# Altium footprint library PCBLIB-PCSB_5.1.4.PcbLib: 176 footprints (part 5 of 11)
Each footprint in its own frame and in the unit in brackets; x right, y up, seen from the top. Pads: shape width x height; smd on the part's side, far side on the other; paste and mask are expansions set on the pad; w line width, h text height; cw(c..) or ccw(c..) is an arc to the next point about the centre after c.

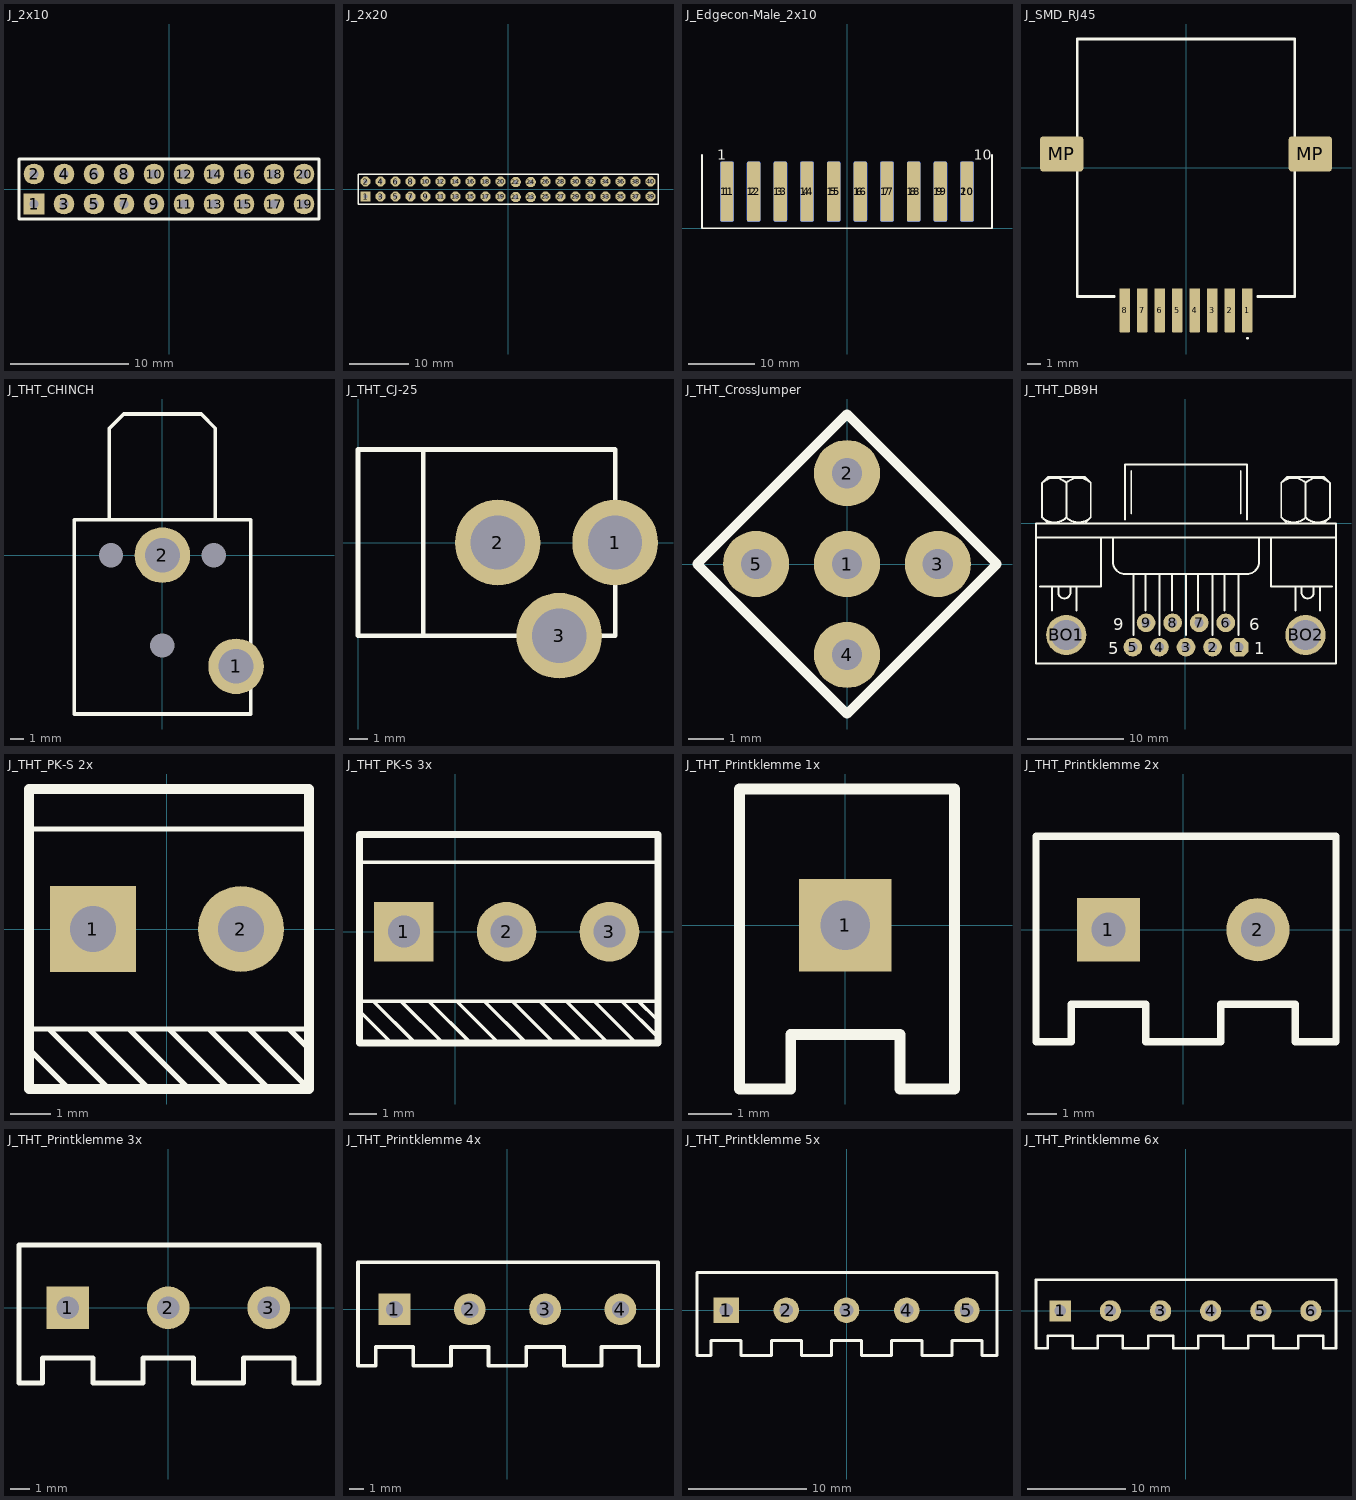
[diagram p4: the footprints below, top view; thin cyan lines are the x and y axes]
## J_2x10 [mm] "LB-2024-4-19"
pads (20):
  rect 1.75x1.75 hole 0.75: 1(-11.43,-1.27)
  round 1.75 hole 0.75: 2(-11.43,1.27) 3(-8.89,-1.27) 4(-8.89,1.27) 5(-6.35,-1.27) 6(-6.35,1.27) 7(-3.81,-1.27) 8(-3.81,1.27) 9(-1.27,-1.27) 10(-1.27,1.27) 11(1.27,-1.27) 12(1.27,1.27) 13(3.81,-1.27) 14(3.81,1.27) 15(6.35,-1.27) 16(6.35,1.27) 17(8.89,-1.27) 18(8.89,1.27) 19(11.43,-1.27) 20(11.43,1.27)
Top Overlay:
  lines w0.254: -12.7,-2.54 12.7,-2.54 12.7,2.54 -12.7,2.54 -12.7,-2.54

## J_2x20 [mm] "LB-2024-4-19"
pads (40):
  rect 1.75x1.75 hole 0.75: 1(-24.13,-1.224)
  round 1.75 hole 0.75: 2(-24.13,1.316) 3(-21.59,-1.224) 4(-21.59,1.316) 5(-19.05,-1.224) 6(-19.05,1.316) 7(-16.51,-1.224) 8(-16.51,1.316) 9(-13.97,-1.224) 10(-13.97,1.316) 11(-11.43,-1.224) 12(-11.43,1.316) 13(-8.89,-1.224) 14(-8.89,1.316) 15(-6.35,-1.224) 16(-6.35,1.316) 17(-3.81,-1.224) 18(-3.81,1.316) 19(-1.27,-1.224) 20(-1.27,1.316) 21(1.296,-1.316) 22(1.296,1.224) 23(3.836,-1.316) 24(3.836,1.224) 25(6.35,-1.224) 26(6.35,1.316) 27(8.89,-1.224) 28(8.89,1.316) 29(11.43,-1.224) 30(11.43,1.316) 31(13.97,-1.224) 32(13.97,1.316) 33(16.51,-1.224) 34(16.51,1.316) 35(19.05,-1.224) 36(19.05,1.316) 37(21.59,-1.224) 38(21.59,1.316) 39(24.13,-1.224) 40(24.13,1.316)
Top Overlay:
  lines w0.254: -25.4,-2.494 25.4,-2.494 25.4,2.586 -25.4,2.586 -25.4,-2.494

## J_Edgecon-Male_2x10 [mm] "PS-2024-06-15"
pads (20):
  rrect25% 2x9 smd paste-0.02 mask+0.05: 1(-18,5.5) 2(-14,5.5) 3(-10,5.5) 4(-6,5.5) 5(-2,5.5) 6(2,5.5) 7(6,5.5) 8(10,5.5) 9(14,5.5) 10(18,5.5)
  rrect25% 2x9 smd far side paste-0.02 mask+0.05: 11(-18,5.5) 12(-14,5.5) 13(-10,5.5) 14(-6,5.5) 15(-2,5.5) 16(2,5.5) 17(6,5.5) 18(10,5.5) 19(14,5.5) 20(18,5.5)
Bottom Layer:
  lines w0.254: -18,8.75 -18,9
Top Overlay:
  lines w0.254: -21.75,11 -21.75,10.75 -21.75,0 0,0 21.75,0 21.75,11
  text "1" at -19.496,10.254 h1.52
  text "10" at 19.004,10.254 h1.52
Bottom Overlay:
  text "11" at -18.754,10.254 h1.52
  text "20" at 21.496,10.254 h1.52

## J_SMD_RJ45 [mm] "LB-2024-05-31"
pads (10):
  rrect15% 0.76x3.185 smd paste-0.02 mask+0.05: 1(4.445,-10.325) 2(3.175,-10.325) 3(1.905,-10.325) 4(0.635,-10.325) 5(-0.635,-10.325) 6(-1.905,-10.325) 7(-3.175,-10.325) 8(-4.445,-10.325)
  rrect15% 3.12x2.54 smd paste-0.02 mask+0.05: MP(-9,1) MP(9,1)
Top Overlay:
  lines w0.1: 4.445,-12.4 cw(c4.445,-12.35) 4.445,-12.3 cw(c4.445,-12.35) 4.445,-12.4
  lines w0.2: -5.2,-9.325 -7.87,-9.325 -7.87,2.6 -7.87,5.8 -7.87,9.325 7.87,9.325 7.87,2.6 7.87,-9.325 5.2,-9.325

## J_THT_CHINCH [mm] "LB-2024-04-19"
pads (5):
  round 4 hole 2.5: 1(5.3,-8) 2(0,0)
  round 0.5 hole 1.75: 3(-3.7,0) 3(0,-6.5) 3(3.7,0)
Top Overlay:
  lines w0.254: -3.81,2.54 -3.81,9.144 -2.794,10.16 2.794,10.16 3.81,9.144 3.81,2.54 ; -6.35,-11.43 -6.35,2.54 -5.08,2.54 5.08,2.54 6.35,2.54 6.35,-11.43 -6.35,-11.43

## J_THT_CJ-25 [mm] "LB-2024-04-19"
height 1.7
pads (3):
  round 4.6 hole 2.9: 1(13.8,0) 2(7.5,0) 3(10.8,-5)
Top Overlay:
  lines w0.254: 3.5,-5 3.5,5 ; 0,-5 0,5 13.8,5 13.8,-5 0,-5

## J_THT_CrossJumper [mm] "LB-2024-04-19"
pads (5):
  round 1.85 hole 0.85: 1(0,0) 2(0,2.54) 3(2.54,0) 4(0,-2.54) 5(-2.54,0)
Top Overlay:
  lines w0.254: -4.191,0 0,-4.191 4.191,0 0,4.191 -4.191,0

## J_THT_DB9H [mm] "LB-2024-04-17"
pads (11):
  oct 1.95x1.95 hole 0.95: 1(5.6,-12.937)
  round 1.95 hole 0.95: 2(2.827,-12.937) 3(0.054,-12.937) 4(-2.718,-12.937) 5(-5.491,-12.937) 6(4.203,-10.397) 7(1.43,-10.397) 8(-1.343,-10.397) 9(-4.115,-10.397)
  round 4.2 hole 3.15: BO1(-12.455,-11.667) BO2(12.543,-11.667)
Top Overlay:
  lines w0.203: -15.609,-1.507 15.718,-1.507 ; -15.186,-6.587 -8.836,-6.587 -8.836,-1.507 ; -14.976,0.608 ccw(c-13.704,1.88) -12.432,0.608 ; -14.976,4.211 cw(c-13.704,2.938) -12.432,4.211 ; -14.339,-0.025 -14.974,0.61 -14.974,4.208 -14.339,4.843 -10.529,4.843 -9.894,4.208 -9.894,0.61 -10.529,-0.025 ; -13.916,-9.127 -13.916,-6.587 ; -13.281,-6.587 -13.281,-7.222 ccw(c-12.646,-7.222) -12.011,-7.222 -12.011,-6.587 ; -12.436,0.608 ccw(c-11.164,1.88) -9.892,0.608 ; -12.436,4.211 cw(c-11.164,2.938) -9.892,4.211 ; -12.434,0.61 -12.434,4.208 ; -11.376,-9.127 -11.376,-6.587 ; -7.566,-1.507 -7.566,-4.047 ccw(c-6.296,-4.047) -6.296,-5.317 6.404,-5.317 ccw(c6.404,-4.047) 7.674,-4.047 7.674,-1.507 ; -6.296,0.398 -6.296,6.113 6.404,6.113 6.404,0.398 ; -5.661,1.033 -5.661,5.478 ; -5.449,-11.667 -5.449,-5.317 ; -4.179,-9.127 -4.179,-5.317 ; -2.697,-11.667 -2.697,-5.317 ; -1.427,-9.127 -1.427,-5.317 ; 0.054,-11.667 0.054,-5.317 ; 1.324,-9.127 1.324,-5.317 ; 2.806,-11.667 2.806,-5.317 ; 4.076,-9.127 4.076,-8.915 4.076,-5.317 ; 5.558,-11.667 5.558,-5.317 ; 5.769,1.033 5.769,5.478 ; 8.944,-1.507 8.944,-6.587 15.294,-6.587 ; 10,0.608 ccw(c11.273,1.88) 12.545,0.608 ; 10,4.211 cw(c11.273,2.938) 12.545,4.211 ; 10.638,-0.025 10.003,0.61 10.003,4.208 10.638,4.843 14.448,4.843 15.083,4.208 15.083,0.61 14.448,-0.025 ; 11.484,-9.127 11.484,-6.587 ; 12.119,-6.587 12.119,-7.222 ccw(c12.754,-7.222) 13.389,-7.222 13.389,-6.587 ; 12.54,0.608 ccw(c13.813,1.88) 15.085,0.608 ; 12.54,4.211 cw(c13.813,2.938) 15.085,4.211 ; 12.543,0.61 12.543,4.208 ; 14.024,-9.127 14.024,-6.587 ; -15.609,-14.63 -15.609,-0.025 15.718,-0.025 15.718,-14.63 -15.609,-14.63
  text "9" at -7.566,-11.159 h1.27
  text "5" at -8.074,-13.699 h1.27
  text "1" at 7.166,-13.699 h1.27
  text "6" at 6.658,-11.159 h1.27

## J_THT_PK-S 2x [mm] "LB-2024-05-03g"
pads (2):
  rect 2.15x2.15 hole 1.15: 1(-1.85,0)
  round 2.15 hole 1.15: 2(1.85,0)
Top Overlay:
  lines w0.127: -3.45,2.5 3.55,2.5 ; -2.45,-4 -3.45,-3 -3.45,-2.5 3.55,-2.5 ; -1.95,-2.5 -0.45,-4 ; -1.45,-4 -2.95,-2.5 ; -0.95,-2.5 0.55,-4 ; 0.05,-2.5 1.55,-4 ; 1.05,-2.5 2.55,-4 ; 3.55,-4 2.05,-2.5 ; 3.55,-3 3.05,-2.5 ; -2.95,-2.5 -2.95,-2.5 ; 2.05,-2.5 2.05,-2.5 ; 3.05,-2.5 3.05,-2.5 ; 3.05,-2.5 3.05,-2.5
  lines w0.254: -3.45,-4 -3.45,2.365 -3.45,3.5 3.55,3.5 3.55,-4 -2.91,-4 -3.45,-4

## J_THT_PK-S 3x [mm] "LB-2024-05-03g"
pads (3):
  rect 2.15x2.15 hole 1.15: 1(-1.85,0)
  round 2.15 hole 1.15: 2(1.85,0) 3(5.55,0)
Top Overlay:
  lines w0.127: -3.5,-2.5 6.5,-2.5 7.3,-2.5 ; -3.45,2.5 7.3,2.5 ; -3.4,-2.9 -2.3,-4 ; -1.95,-2.5 -0.45,-4 ; -1.45,-4 -2.95,-2.5 ; -0.95,-2.5 0.55,-4 ; 0.05,-2.5 1.55,-4 ; 1.05,-2.5 2.55,-4 ; 3.55,-4 2.05,-2.5 ; 4,-2.5 5.425,-3.925 ; 4.575,-4.025 3.05,-2.5 ; 5,-2.5 6.5,-4 ; 6,-2.5 7.3,-3.8 ; 7,-2.5 6.6,-2.5 7.25,-3.15 ; -2.95,-2.5 -2.95,-2.5 ; 2.05,-2.5 2.05,-2.5 ; 3.05,-2.5 3.05,-2.5 ; 3.05,-2.5 3.05,-2.5
  lines w0.254: -3.45,-4 -3.45,2.365 -3.45,3.5 7.3,3.5 7.3,-4 3.55,-4 -2.91,-4 -3.45,-4

## J_THT_Printklemme 1x [mm] "LB-2024-04-17"
pads (1):
  rect 2.15x2.15 hole 1.15: 1(0,0)
Top Overlay:
  lines w0.254: -2.46,-3.81 -2.46,2.365 -2.46,3.175 2.54,3.175 2.54,-3.81 1.27,-3.81 1.27,-2.54 -1.27,-2.54 -1.27,-3.81 -2.46,-3.81

## J_THT_Printklemme 2x [mm] "LB-2024-04-17"
pads (2):
  rect 2.15x2.15 hole 1.15: 1(-2.54,0)
  round 2.15 hole 1.15: 2(2.54,0)
Top Overlay:
  lines w0.254: 1.27,-3.81 1.27,-2.54 ; 1.27,-3.81 -1.27,-3.81 -1.27,-2.54 -3.81,-2.54 -3.81,-3.81 -5,-3.81 -5,2.365 -5,3.175 5.19,3.175 5.19,-3.81 3.81,-3.81 ; 1.27,-3.81 1.27,-2.54 ; 1.27,-2.54 3.81,-2.54 ; 3.81,-3.81 3.81,-2.54 ; 3.81,-3.81 3.81,-2.54

## J_THT_Printklemme 3x [mm] "LB-2024-04-17"
pads (3):
  rect 2.15x2.15 hole 1.15: 1(-5.08,0)
  round 2.15 hole 1.15: 2(0,0) 3(5.08,0)
Top Overlay:
  lines w0.254: -1.27,-3.81 -1.27,-2.54 ; -1.27,-3.81 -3.81,-3.81 -3.81,-2.54 -6.35,-2.54 -6.35,-3.81 -7.54,-3.81 -7.54,2.365 -7.54,3.175 2.65,3.175 7.62,3.175 7.62,-3.81 6.35,-3.81 6.35,-2.54 3.81,-2.54 3.81,-3.81 1.27,-3.81 ; -1.27,-3.81 -1.27,-2.54 ; -1.27,-2.54 1.27,-2.54 ; 1.27,-3.81 1.27,-2.54 ; 1.27,-3.81 1.27,-2.54

## J_THT_Printklemme 4x [mm] "LB-2024-04-17"
pads (4):
  rect 2.15x2.15 hole 1.15: 1(-7.62,0)
  round 2.15 hole 1.15: 2(-2.54,0) 3(2.54,0) 4(7.62,0)
Top Overlay:
  lines w0.254: -3.81,-3.81 -3.81,-2.54 ; -3.81,-3.81 -6.35,-3.81 -6.35,-2.54 -8.89,-2.54 -8.89,-3.81 -10.08,-3.81 -10.08,2.365 -10.08,3.175 0.11,3.175 10.16,3.175 10.16,-3.81 8.89,-3.81 8.89,-2.54 6.35,-2.54 6.35,-3.81 3.81,-3.81 3.81,-2.54 1.27,-2.54 1.27,-3.81 -1.27,-3.81 ; -3.81,-3.81 -3.81,-2.54 ; -3.81,-2.54 -1.27,-2.54 ; -1.27,-3.81 -1.27,-2.54 ; -1.27,-3.81 -1.27,-2.54

## J_THT_Printklemme 5x [mm] "LB-2024-04-17"
pads (5):
  rect 2.15x2.15 hole 1.15: 1(-10.16,0)
  round 2.15 hole 1.15: 2(-5.08,0) 3(0,0) 4(5.08,0) 5(10.16,0)
Top Overlay:
  lines w0.254: -6.35,-3.81 -6.35,-2.54 ; -6.35,-3.81 -8.89,-3.81 -8.89,-2.54 -11.43,-2.54 -11.43,-3.81 -12.62,-3.81 -12.62,2.365 -12.62,3.175 -2.43,3.175 12.7,3.175 12.7,-3.81 11.43,-3.81 11.43,-2.54 8.89,-2.54 8.89,-3.81 6.35,-3.81 6.35,-2.54 3.81,-2.54 3.81,-3.81 1.27,-3.81 1.27,-2.54 -1.27,-2.54 -1.27,-3.81 -3.81,-3.81 ; -6.35,-3.81 -6.35,-2.54 ; -6.35,-2.54 -3.81,-2.54 ; -3.81,-3.81 -3.81,-2.54 ; -3.81,-3.81 -3.81,-2.54

## J_THT_Printklemme 6x [mm] "LB-2024-04-17"
pads (6):
  rect 2.15x2.15 hole 1.15: 1(-12.7,0)
  round 2.15 hole 1.15: 2(-7.62,0) 3(-2.54,0) 4(2.54,0) 5(7.62,0) 6(12.7,0)
Top Overlay:
  lines w0.254: -8.89,-3.81 -8.89,-2.54 ; -8.89,-3.81 -11.43,-3.81 -11.43,-2.54 -13.97,-2.54 -13.97,-3.81 -15.16,-3.81 -15.16,2.365 -15.16,3.175 -4.97,3.175 15.24,3.175 15.24,-3.81 13.97,-3.81 13.97,-2.54 11.43,-2.54 11.43,-3.81 8.89,-3.81 8.89,-2.54 6.35,-2.54 6.35,-3.81 3.81,-3.81 3.81,-2.54 1.27,-2.54 1.27,-3.81 -1.27,-3.81 -1.27,-2.54 -3.81,-2.54 -3.81,-3.81 -6.35,-3.81 ; -8.89,-3.81 -8.89,-2.54 ; -8.89,-2.54 -6.35,-2.54 ; -6.35,-3.81 -6.35,-2.54 ; -6.35,-3.81 -6.35,-2.54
